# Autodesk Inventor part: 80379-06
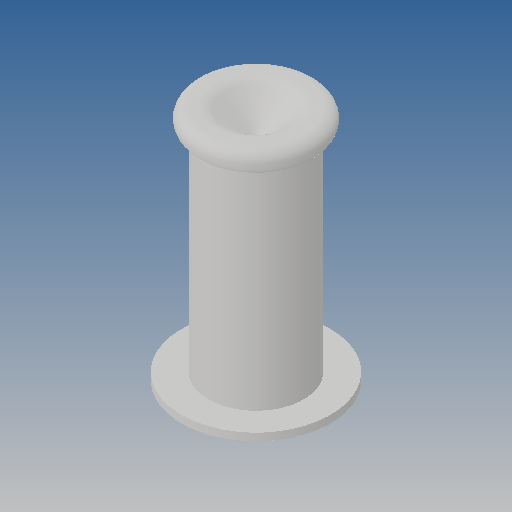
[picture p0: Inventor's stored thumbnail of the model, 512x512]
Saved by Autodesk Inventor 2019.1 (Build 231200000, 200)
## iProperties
Created: 2010-06
Part Number: 80379-06
Material: Ogólny
Document SubType Name: Modeling
Designer: CADENGINEERING4
Density: 1 g/cm^3
Appearance: Domyślna
Author: CADENGINEERING4
Revision Number: ÈÎºÎ
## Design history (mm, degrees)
feature "NONE"
node "Bryła1"
